VERSION 5.7 ;
  NOWIREEXTENSIONATPIN ON ;
  DIVIDERCHAR "/" ;
  BUSBITCHARS "[]" ;
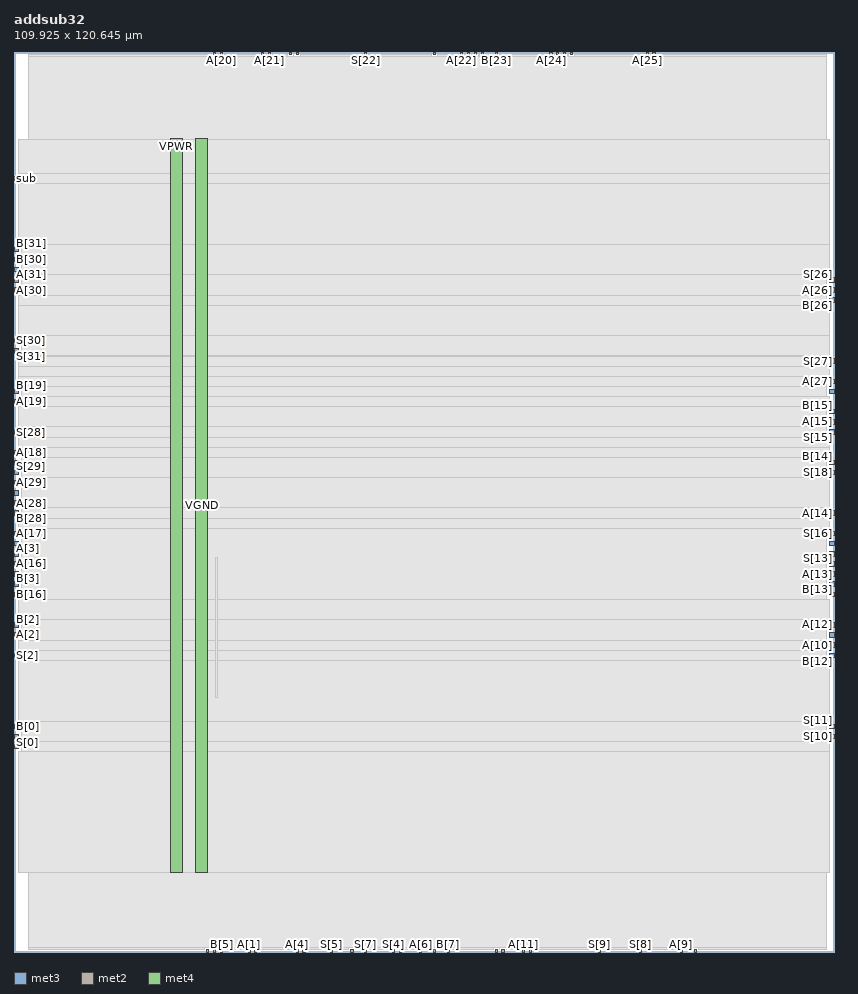
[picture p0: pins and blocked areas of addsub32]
MACRO addsub32
  CLASS BLOCK ;
  FOREIGN addsub32 ;
  ORIGIN 0.000 0.000 ;
  SIZE 109.925 BY 120.645 ;
  PIN A[0]
    DIRECTION INPUT ;
    USE SIGNAL ;
    ANTENNAGATEAREA 0.213000 ;
    PORT
      LAYER met3 ;
        RECT 0.000 27.240 0.600 27.840 ;
    END
  END A[0]
  PIN A[10]
    DIRECTION INPUT ;
    USE SIGNAL ;
    ANTENNAGATEAREA 0.213000 ;
    PORT
      LAYER met3 ;
        RECT 109.325 40.840 109.925 41.440 ;
    END
  END A[10]
  PIN A[11]
    DIRECTION INPUT ;
    USE SIGNAL ;
    ANTENNAGATEAREA 0.213000 ;
    PORT
      LAYER met2 ;
        RECT 68.170 0.000 68.450 0.280 ;
    END
  END A[11]
  PIN A[12]
    DIRECTION INPUT ;
    USE SIGNAL ;
    ANTENNAGATEAREA 0.213000 ;
    PORT
      LAYER met3 ;
        RECT 109.325 43.560 109.925 44.160 ;
    END
  END A[12]
  PIN A[13]
    DIRECTION INPUT ;
    USE SIGNAL ;
    ANTENNAGATEAREA 0.213000 ;
    PORT
      LAYER met3 ;
        RECT 109.325 50.360 109.925 50.960 ;
    END
  END A[13]
  PIN A[14]
    DIRECTION INPUT ;
    USE SIGNAL ;
    ANTENNAGATEAREA 0.213000 ;
    PORT
      LAYER met3 ;
        RECT 109.325 58.520 109.925 59.120 ;
    END
  END A[14]
  PIN A[15]
    DIRECTION INPUT ;
    USE SIGNAL ;
    ANTENNAGATEAREA 0.213000 ;
    PORT
      LAYER met3 ;
        RECT 109.325 70.760 109.925 71.360 ;
    END
  END A[15]
  PIN A[16]
    DIRECTION INPUT ;
    USE SIGNAL ;
    ANTENNAGATEAREA 0.213000 ;
    PORT
      LAYER met3 ;
        RECT 0.000 51.720 0.600 52.320 ;
    END
  END A[16]
  PIN A[17]
    DIRECTION INPUT ;
    USE SIGNAL ;
    ANTENNAGATEAREA 0.213000 ;
    PORT
      LAYER met3 ;
        RECT 0.000 55.800 0.600 56.400 ;
    END
  END A[17]
  PIN A[18]
    DIRECTION INPUT ;
    USE SIGNAL ;
    ANTENNAGATEAREA 0.213000 ;
    PORT
      LAYER met3 ;
        RECT 0.000 66.680 0.600 67.280 ;
    END
  END A[18]
  PIN A[19]
    DIRECTION INPUT ;
    USE SIGNAL ;
    ANTENNAGATEAREA 0.213000 ;
    PORT
      LAYER met3 ;
        RECT 0.000 73.480 0.600 74.080 ;
    END
  END A[19]
  PIN A[1]
    DIRECTION INPUT ;
    USE SIGNAL ;
    ANTENNAGATEAREA 0.213000 ;
    PORT
      LAYER met2 ;
        RECT 31.370 0.000 31.650 0.280 ;
    END
  END A[1]
  PIN A[20]
    DIRECTION INPUT ;
    USE SIGNAL ;
    ANTENNAGATEAREA 0.213000 ;
    PORT
      LAYER met2 ;
        RECT 27.690 120.365 27.970 120.645 ;
    END
  END A[20]
  PIN A[21]
    DIRECTION INPUT ;
    USE SIGNAL ;
    ANTENNAGATEAREA 0.213000 ;
    PORT
      LAYER met2 ;
        RECT 34.130 120.365 34.410 120.645 ;
    END
  END A[21]
  PIN A[22]
    DIRECTION INPUT ;
    USE SIGNAL ;
    ANTENNAGATEAREA 0.213000 ;
    PORT
      LAYER met2 ;
        RECT 59.890 120.365 60.170 120.645 ;
    END
  END A[22]
  PIN A[23]
    DIRECTION INPUT ;
    USE SIGNAL ;
    ANTENNAGATEAREA 0.213000 ;
    PORT
      LAYER met2 ;
        RECT 60.810 120.365 61.090 120.645 ;
    END
  END A[23]
  PIN A[24]
    DIRECTION INPUT ;
    USE SIGNAL ;
    ANTENNAGATEAREA 0.213000 ;
    PORT
      LAYER met2 ;
        RECT 71.850 120.365 72.130 120.645 ;
    END
  END A[24]
  PIN A[25]
    DIRECTION INPUT ;
    USE SIGNAL ;
    ANTENNAGATEAREA 0.213000 ;
    PORT
      LAYER met2 ;
        RECT 84.730 120.365 85.010 120.645 ;
    END
  END A[25]
  PIN A[26]
    DIRECTION INPUT ;
    USE SIGNAL ;
    ANTENNAGATEAREA 0.213000 ;
    PORT
      LAYER met3 ;
        RECT 109.325 88.440 109.925 89.040 ;
    END
  END A[26]
  PIN A[27]
    DIRECTION INPUT ;
    USE SIGNAL ;
    ANTENNAGATEAREA 0.213000 ;
    PORT
      LAYER met3 ;
        RECT 109.325 76.200 109.925 76.800 ;
    END
  END A[27]
  PIN A[28]
    DIRECTION INPUT ;
    USE SIGNAL ;
    ANTENNAGATEAREA 0.213000 ;
    PORT
      LAYER met3 ;
        RECT 0.000 59.880 0.600 60.480 ;
    END
  END A[28]
  PIN A[29]
    DIRECTION INPUT ;
    USE SIGNAL ;
    ANTENNAGATEAREA 0.213000 ;
    PORT
      LAYER met3 ;
        RECT 0.000 62.600 0.600 63.200 ;
    END
  END A[29]
  PIN A[2]
    DIRECTION INPUT ;
    USE SIGNAL ;
    ANTENNAGATEAREA 0.213000 ;
    PORT
      LAYER met3 ;
        RECT 0.000 42.200 0.600 42.800 ;
    END
  END A[2]
  PIN A[30]
    DIRECTION INPUT ;
    USE SIGNAL ;
    ANTENNAGATEAREA 0.213000 ;
    PORT
      LAYER met3 ;
        RECT 0.000 88.440 0.600 89.040 ;
    END
  END A[30]
  PIN A[31]
    DIRECTION INPUT ;
    USE SIGNAL ;
    ANTENNAGATEAREA 0.213000 ;
    PORT
      LAYER met3 ;
        RECT 0.000 89.800 0.600 90.400 ;
    END
  END A[31]
  PIN A[3]
    DIRECTION INPUT ;
    USE SIGNAL ;
    ANTENNAGATEAREA 0.213000 ;
    PORT
      LAYER met3 ;
        RECT 0.000 53.080 0.600 53.680 ;
    END
  END A[3]
  PIN A[4]
    DIRECTION INPUT ;
    USE SIGNAL ;
    ANTENNAGATEAREA 0.213000 ;
    PORT
      LAYER met2 ;
        RECT 37.810 0.000 38.090 0.280 ;
    END
  END A[4]
  PIN A[5]
    DIRECTION INPUT ;
    USE SIGNAL ;
    ANTENNAGATEAREA 0.213000 ;
    PORT
      LAYER met2 ;
        RECT 26.770 0.000 27.050 0.280 ;
    END
  END A[5]
  PIN A[6]
    DIRECTION INPUT ;
    USE SIGNAL ;
    ANTENNAGATEAREA 0.213000 ;
    PORT
      LAYER met2 ;
        RECT 54.370 0.000 54.650 0.280 ;
    END
  END A[6]
  PIN A[7]
    DIRECTION INPUT ;
    USE SIGNAL ;
    ANTENNAGATEAREA 0.213000 ;
    PORT
      LAYER met2 ;
        RECT 56.210 0.000 56.490 0.280 ;
    END
  END A[7]
  PIN A[8]
    DIRECTION INPUT ;
    USE SIGNAL ;
    ANTENNAGATEAREA 0.213000 ;
    PORT
      LAYER met2 ;
        RECT 65.410 0.000 65.690 0.280 ;
    END
  END A[8]
  PIN A[9]
    DIRECTION INPUT ;
    USE SIGNAL ;
    ANTENNAGATEAREA 0.213000 ;
    PORT
      LAYER met2 ;
        RECT 89.330 0.000 89.610 0.280 ;
    END
  END A[9]
  PIN B[0]
    DIRECTION INPUT ;
    USE SIGNAL ;
    ANTENNAGATEAREA 0.126000 ;
    PORT
      LAYER met3 ;
        RECT 0.000 29.960 0.600 30.560 ;
    END
  END B[0]
  PIN B[10]
    DIRECTION INPUT ;
    USE SIGNAL ;
    ANTENNAGATEAREA 0.213000 ;
    PORT
      LAYER met3 ;
        RECT 109.325 42.200 109.925 42.800 ;
    END
  END B[10]
  PIN B[11]
    DIRECTION INPUT ;
    USE SIGNAL ;
    ANTENNAGATEAREA 0.213000 ;
    PORT
      LAYER met2 ;
        RECT 69.090 0.000 69.370 0.280 ;
    END
  END B[11]
  PIN B[12]
    DIRECTION INPUT ;
    USE SIGNAL ;
    ANTENNAGATEAREA 0.213000 ;
    PORT
      LAYER met3 ;
        RECT 109.325 39.480 109.925 40.080 ;
    END
  END B[12]
  PIN B[13]
    DIRECTION INPUT ;
    USE SIGNAL ;
    ANTENNAGATEAREA 0.213000 ;
    PORT
      LAYER met3 ;
        RECT 109.325 49.000 109.925 49.600 ;
    END
  END B[13]
  PIN B[14]
    DIRECTION INPUT ;
    USE SIGNAL ;
    ANTENNAGATEAREA 0.213000 ;
    PORT
      LAYER met3 ;
        RECT 109.325 65.320 109.925 65.920 ;
    END
  END B[14]
  PIN B[15]
    DIRECTION INPUT ;
    USE SIGNAL ;
    ANTENNAGATEAREA 0.213000 ;
    PORT
      LAYER met3 ;
        RECT 109.325 72.120 109.925 72.720 ;
    END
  END B[15]
  PIN B[16]
    DIRECTION INPUT ;
    USE SIGNAL ;
    ANTENNAGATEAREA 0.213000 ;
    PORT
      LAYER met3 ;
        RECT 0.000 47.640 0.600 48.240 ;
    END
  END B[16]
  PIN B[17]
    DIRECTION INPUT ;
    USE SIGNAL ;
    ANTENNAGATEAREA 0.213000 ;
    PORT
      LAYER met3 ;
        RECT 0.000 54.440 0.600 55.040 ;
    END
  END B[17]
  PIN B[18]
    DIRECTION INPUT ;
    USE SIGNAL ;
    ANTENNAGATEAREA 0.213000 ;
    PORT
      LAYER met3 ;
        RECT 0.000 65.320 0.600 65.920 ;
    END
  END B[18]
  PIN B[19]
    DIRECTION INPUT ;
    USE SIGNAL ;
    ANTENNAGATEAREA 0.213000 ;
    PORT
      LAYER met3 ;
        RECT 0.000 74.840 0.600 75.440 ;
    END
  END B[19]
  PIN B[1]
    DIRECTION INPUT ;
    USE SIGNAL ;
    ANTENNAGATEAREA 0.213000 ;
    PORT
      LAYER met2 ;
        RECT 32.290 0.000 32.570 0.280 ;
    END
  END B[1]
  PIN B[20]
    DIRECTION INPUT ;
    USE SIGNAL ;
    ANTENNAGATEAREA 0.213000 ;
    PORT
      LAYER met2 ;
        RECT 26.770 120.365 27.050 120.645 ;
    END
  END B[20]
  PIN B[21]
    DIRECTION INPUT ;
    USE SIGNAL ;
    ANTENNAGATEAREA 0.213000 ;
    PORT
      LAYER met2 ;
        RECT 33.210 120.365 33.490 120.645 ;
    END
  END B[21]
  PIN B[22]
    DIRECTION INPUT ;
    USE SIGNAL ;
    ANTENNAGATEAREA 0.213000 ;
    PORT
      LAYER met2 ;
        RECT 62.650 120.365 62.930 120.645 ;
    END
  END B[22]
  PIN B[23]
    DIRECTION INPUT ;
    USE SIGNAL ;
    ANTENNAGATEAREA 0.213000 ;
    PORT
      LAYER met2 ;
        RECT 64.490 120.365 64.770 120.645 ;
    END
  END B[23]
  PIN B[24]
    DIRECTION INPUT ;
    USE SIGNAL ;
    ANTENNAGATEAREA 0.213000 ;
    PORT
      LAYER met2 ;
        RECT 73.690 120.365 73.970 120.645 ;
    END
  END B[24]
  PIN B[25]
    DIRECTION INPUT ;
    USE SIGNAL ;
    ANTENNAGATEAREA 0.213000 ;
    PORT
      LAYER met2 ;
        RECT 85.650 120.365 85.930 120.645 ;
    END
  END B[25]
  PIN B[26]
    DIRECTION INPUT ;
    USE SIGNAL ;
    ANTENNAGATEAREA 0.213000 ;
    PORT
      LAYER met3 ;
        RECT 109.325 87.080 109.925 87.680 ;
    END
  END B[26]
  PIN B[27]
    DIRECTION INPUT ;
    USE SIGNAL ;
    ANTENNAGATEAREA 0.213000 ;
    PORT
      LAYER met3 ;
        RECT 109.325 74.840 109.925 75.440 ;
    END
  END B[27]
  PIN B[28]
    DIRECTION INPUT ;
    USE SIGNAL ;
    ANTENNAGATEAREA 0.213000 ;
    PORT
      LAYER met3 ;
        RECT 0.000 58.520 0.600 59.120 ;
    END
  END B[28]
  PIN B[29]
    DIRECTION INPUT ;
    USE SIGNAL ;
    ANTENNAGATEAREA 0.213000 ;
    PORT
      LAYER met3 ;
        RECT 0.000 61.240 0.600 61.840 ;
    END
  END B[29]
  PIN B[2]
    DIRECTION INPUT ;
    USE SIGNAL ;
    ANTENNAGATEAREA 0.213000 ;
    PORT
      LAYER met3 ;
        RECT 0.000 43.560 0.600 44.160 ;
    END
  END B[2]
  PIN B[30]
    DIRECTION INPUT ;
    USE SIGNAL ;
    ANTENNAGATEAREA 0.213000 ;
    PORT
      LAYER met3 ;
        RECT 0.000 92.520 0.600 93.120 ;
    END
  END B[30]
  PIN B[31]
    DIRECTION INPUT ;
    USE SIGNAL ;
    ANTENNAGATEAREA 0.213000 ;
    PORT
      LAYER met3 ;
        RECT 0.000 93.880 0.600 94.480 ;
    END
  END B[31]
  PIN B[3]
    DIRECTION INPUT ;
    USE SIGNAL ;
    ANTENNAGATEAREA 0.213000 ;
    PORT
      LAYER met3 ;
        RECT 0.000 49.000 0.600 49.600 ;
    END
  END B[3]
  PIN B[4]
    DIRECTION INPUT ;
    USE SIGNAL ;
    ANTENNAGATEAREA 0.213000 ;
    PORT
      LAYER met2 ;
        RECT 38.730 0.000 39.010 0.280 ;
    END
  END B[4]
  PIN B[5]
    DIRECTION INPUT ;
    USE SIGNAL ;
    ANTENNAGATEAREA 0.213000 ;
    PORT
      LAYER met2 ;
        RECT 27.690 0.000 27.970 0.280 ;
    END
  END B[5]
  PIN B[6]
    DIRECTION INPUT ;
    USE SIGNAL ;
    ANTENNAGATEAREA 0.213000 ;
    PORT
      LAYER met2 ;
        RECT 51.610 0.000 51.890 0.280 ;
    END
  END B[6]
  PIN B[7]
    DIRECTION INPUT ;
    USE SIGNAL ;
    ANTENNAGATEAREA 0.213000 ;
    PORT
      LAYER met2 ;
        RECT 58.050 0.000 58.330 0.280 ;
    END
  END B[7]
  PIN B[8]
    DIRECTION INPUT ;
    USE SIGNAL ;
    ANTENNAGATEAREA 0.213000 ;
    PORT
      LAYER met2 ;
        RECT 64.490 0.000 64.770 0.280 ;
    END
  END B[8]
  PIN B[9]
    DIRECTION INPUT ;
    USE SIGNAL ;
    ANTENNAGATEAREA 0.213000 ;
    PORT
      LAYER met2 ;
        RECT 91.170 0.000 91.450 0.280 ;
    END
  END B[9]
  PIN S[0]
    DIRECTION OUTPUT ;
    USE SIGNAL ;
    ANTENNADIFFAREA 0.702900 ;
    PORT
      LAYER met3 ;
        RECT 0.000 28.600 0.600 29.200 ;
    END
  END S[0]
  PIN S[10]
    DIRECTION OUTPUT ;
    USE SIGNAL ;
    ANTENNAGATEAREA 0.126000 ;
    ANTENNADIFFAREA 0.429000 ;
    PORT
      LAYER met3 ;
        RECT 109.325 28.600 109.925 29.200 ;
    END
  END S[10]
  PIN S[11]
    DIRECTION OUTPUT ;
    USE SIGNAL ;
    ANTENNADIFFAREA 0.383400 ;
    PORT
      LAYER met3 ;
        RECT 109.325 29.960 109.925 30.560 ;
    END
  END S[11]
  PIN S[12]
    DIRECTION OUTPUT ;
    USE SIGNAL ;
    ANTENNAGATEAREA 0.126000 ;
    ANTENNADIFFAREA 0.429000 ;
    PORT
      LAYER met3 ;
        RECT 109.325 47.640 109.925 48.240 ;
    END
  END S[12]
  PIN S[13]
    DIRECTION OUTPUT ;
    USE SIGNAL ;
    ANTENNAGATEAREA 0.126000 ;
    ANTENNADIFFAREA 0.429000 ;
    PORT
      LAYER met3 ;
        RECT 109.325 51.720 109.925 52.320 ;
    END
  END S[13]
  PIN S[14]
    DIRECTION OUTPUT ;
    USE SIGNAL ;
    ANTENNADIFFAREA 0.795200 ;
    PORT
      LAYER met3 ;
        RECT 109.325 53.080 109.925 53.680 ;
    END
  END S[14]
  PIN S[15]
    DIRECTION OUTPUT ;
    USE SIGNAL ;
    ANTENNADIFFAREA 0.383400 ;
    PORT
      LAYER met3 ;
        RECT 109.325 69.400 109.925 70.000 ;
    END
  END S[15]
  PIN S[16]
    DIRECTION OUTPUT ;
    USE SIGNAL ;
    ANTENNADIFFAREA 1.336500 ;
    PORT
      LAYER met3 ;
        RECT 109.325 55.800 109.925 56.400 ;
    END
  END S[16]
  PIN S[17]
    DIRECTION OUTPUT ;
    USE SIGNAL ;
    ANTENNADIFFAREA 1.336500 ;
    PORT
      LAYER met3 ;
        RECT 109.325 54.440 109.925 55.040 ;
    END
  END S[17]
  PIN S[18]
    DIRECTION OUTPUT ;
    USE SIGNAL ;
    ANTENNADIFFAREA 0.795200 ;
    PORT
      LAYER met3 ;
        RECT 109.325 63.960 109.925 64.560 ;
    END
  END S[18]
  PIN S[19]
    DIRECTION OUTPUT ;
    USE SIGNAL ;
    ANTENNADIFFAREA 0.795200 ;
    PORT
      LAYER met2 ;
        RECT 56.210 120.365 56.490 120.645 ;
    END
  END S[19]
  PIN S[1]
    DIRECTION OUTPUT ;
    USE SIGNAL ;
    ANTENNAGATEAREA 0.126000 ;
    ANTENNADIFFAREA 0.429000 ;
    PORT
      LAYER met2 ;
        RECT 25.850 0.000 26.130 0.280 ;
    END
  END S[1]
  PIN S[20]
    DIRECTION OUTPUT ;
    USE SIGNAL ;
    ANTENNADIFFAREA 1.336500 ;
    PORT
      LAYER met2 ;
        RECT 37.810 120.365 38.090 120.645 ;
    END
  END S[20]
  PIN S[21]
    DIRECTION OUTPUT ;
    USE SIGNAL ;
    ANTENNADIFFAREA 1.782000 ;
    PORT
      LAYER met2 ;
        RECT 36.890 120.365 37.170 120.645 ;
    END
  END S[21]
  PIN S[22]
    DIRECTION OUTPUT ;
    USE SIGNAL ;
    ANTENNADIFFAREA 1.336500 ;
    PORT
      LAYER met2 ;
        RECT 47.010 120.365 47.290 120.645 ;
    END
  END S[22]
  PIN S[23]
    DIRECTION OUTPUT ;
    USE SIGNAL ;
    ANTENNADIFFAREA 0.891000 ;
    PORT
      LAYER met2 ;
        RECT 61.730 120.365 62.010 120.645 ;
    END
  END S[23]
  PIN S[24]
    DIRECTION OUTPUT ;
    USE SIGNAL ;
    ANTENNADIFFAREA 1.336500 ;
    PORT
      LAYER met2 ;
        RECT 72.770 120.365 73.050 120.645 ;
    END
  END S[24]
  PIN S[25]
    DIRECTION OUTPUT ;
    USE SIGNAL ;
    ANTENNADIFFAREA 1.336500 ;
    PORT
      LAYER met2 ;
        RECT 74.610 120.365 74.890 120.645 ;
    END
  END S[25]
  PIN S[26]
    DIRECTION OUTPUT ;
    USE SIGNAL ;
    ANTENNADIFFAREA 1.336500 ;
    PORT
      LAYER met3 ;
        RECT 109.325 89.800 109.925 90.400 ;
    END
  END S[26]
  PIN S[27]
    DIRECTION OUTPUT ;
    USE SIGNAL ;
    ANTENNADIFFAREA 1.336500 ;
    PORT
      LAYER met3 ;
        RECT 109.325 78.920 109.925 79.520 ;
    END
  END S[27]
  PIN S[28]
    DIRECTION OUTPUT ;
    USE SIGNAL ;
    ANTENNADIFFAREA 1.336500 ;
    PORT
      LAYER met3 ;
        RECT 0.000 69.400 0.600 70.000 ;
    END
  END S[28]
  PIN S[29]
    DIRECTION OUTPUT ;
    USE SIGNAL ;
    ANTENNADIFFAREA 1.336500 ;
    PORT
      LAYER met3 ;
        RECT 0.000 63.960 0.600 64.560 ;
    END
  END S[29]
  PIN S[2]
    DIRECTION OUTPUT ;
    USE SIGNAL ;
    ANTENNADIFFAREA 0.891000 ;
    PORT
      LAYER met3 ;
        RECT 0.000 39.480 0.600 40.080 ;
    END
  END S[2]
  PIN S[30]
    DIRECTION OUTPUT ;
    USE SIGNAL ;
    ANTENNADIFFAREA 1.336500 ;
    PORT
      LAYER met3 ;
        RECT 0.000 81.640 0.600 82.240 ;
    END
  END S[30]
  PIN S[31]
    DIRECTION OUTPUT ;
    USE SIGNAL ;
    ANTENNADIFFAREA 1.336500 ;
    PORT
      LAYER met3 ;
        RECT 0.000 80.280 0.600 80.880 ;
    END
  END S[31]
  PIN S[3]
    DIRECTION OUTPUT ;
    USE SIGNAL ;
    ANTENNADIFFAREA 1.336500 ;
    PORT
      LAYER met3 ;
        RECT 0.000 50.360 0.600 50.960 ;
    END
  END S[3]
  PIN S[4]
    DIRECTION OUTPUT ;
    USE SIGNAL ;
    ANTENNADIFFAREA 0.383400 ;
    PORT
      LAYER met2 ;
        RECT 50.690 0.000 50.970 0.280 ;
    END
  END S[4]
  PIN S[5]
    DIRECTION OUTPUT ;
    USE SIGNAL ;
    ANTENNADIFFAREA 0.445500 ;
    PORT
      LAYER met2 ;
        RECT 42.410 0.000 42.690 0.280 ;
    END
  END S[5]
  PIN S[6]
    DIRECTION OUTPUT ;
    USE SIGNAL ;
    ANTENNADIFFAREA 1.336500 ;
    PORT
      LAYER met2 ;
        RECT 45.170 0.000 45.450 0.280 ;
    END
  END S[6]
  PIN S[7]
    DIRECTION OUTPUT ;
    USE SIGNAL ;
    ANTENNADIFFAREA 0.445500 ;
    PORT
      LAYER met2 ;
        RECT 47.010 0.000 47.290 0.280 ;
    END
  END S[7]
  PIN S[8]
    DIRECTION OUTPUT ;
    USE SIGNAL ;
    ANTENNADIFFAREA 0.383400 ;
    PORT
      LAYER met2 ;
        RECT 83.810 0.000 84.090 0.280 ;
    END
  END S[8]
  PIN S[9]
    DIRECTION OUTPUT ;
    USE SIGNAL ;
    ANTENNADIFFAREA 0.383400 ;
    PORT
      LAYER met2 ;
        RECT 78.290 0.000 78.570 0.280 ;
    END
  END S[9]
  PIN VGND
    DIRECTION INOUT ;
    USE GROUND ;
    PORT
      LAYER met4 ;
        RECT 24.340 10.640 25.940 109.040 ;
    END
  END VGND
  PIN VPWR
    DIRECTION INOUT ;
    USE POWER ;
    PORT
      LAYER met4 ;
        RECT 21.040 10.640 22.640 109.040 ;
    END
  END VPWR
  PIN carryOut
    DIRECTION OUTPUT ;
    USE SIGNAL ;
    ANTENNADIFFAREA 1.336500 ;
    PORT
      LAYER met3 ;
        RECT 0.000 91.160 0.600 91.760 ;
    END
  END carryOut
  PIN sub
    DIRECTION INPUT ;
    USE SIGNAL ;
    ANTENNAGATEAREA 0.742500 ;
    PORT
      LAYER met3 ;
        RECT 0.000 103.400 0.600 104.000 ;
    END
  END sub
  OBS
      LAYER nwell ;
        RECT 5.330 10.795 104.150 108.885 ;
      LAYER li1 ;
        RECT 5.520 10.795 103.960 108.885 ;
      LAYER met1 ;
        RECT 1.910 5.480 108.950 117.940 ;
      LAYER met2 ;
        RECT 1.930 120.085 26.490 120.365 ;
        RECT 27.330 120.085 27.410 120.365 ;
        RECT 28.250 120.085 32.930 120.365 ;
        RECT 33.770 120.085 33.850 120.365 ;
        RECT 34.690 120.085 36.610 120.365 ;
        RECT 37.450 120.085 37.530 120.365 ;
        RECT 38.370 120.085 46.730 120.365 ;
        RECT 47.570 120.085 55.930 120.365 ;
        RECT 56.770 120.085 59.610 120.365 ;
        RECT 60.450 120.085 60.530 120.365 ;
        RECT 61.370 120.085 61.450 120.365 ;
        RECT 62.290 120.085 62.370 120.365 ;
        RECT 63.210 120.085 64.210 120.365 ;
        RECT 65.050 120.085 71.570 120.365 ;
        RECT 72.410 120.085 72.490 120.365 ;
        RECT 73.330 120.085 73.410 120.365 ;
        RECT 74.250 120.085 74.330 120.365 ;
        RECT 75.170 120.085 84.450 120.365 ;
        RECT 85.290 120.085 85.370 120.365 ;
        RECT 86.210 120.085 108.930 120.365 ;
        RECT 1.930 0.560 108.930 120.085 ;
        RECT 1.930 0.280 25.570 0.560 ;
        RECT 26.410 0.280 26.490 0.560 ;
        RECT 27.330 0.280 27.410 0.560 ;
        RECT 28.250 0.280 31.090 0.560 ;
        RECT 31.930 0.280 32.010 0.560 ;
        RECT 32.850 0.280 37.530 0.560 ;
        RECT 38.370 0.280 38.450 0.560 ;
        RECT 39.290 0.280 42.130 0.560 ;
        RECT 42.970 0.280 44.890 0.560 ;
        RECT 45.730 0.280 46.730 0.560 ;
        RECT 47.570 0.280 50.410 0.560 ;
        RECT 51.250 0.280 51.330 0.560 ;
        RECT 52.170 0.280 54.090 0.560 ;
        RECT 54.930 0.280 55.930 0.560 ;
        RECT 56.770 0.280 57.770 0.560 ;
        RECT 58.610 0.280 64.210 0.560 ;
        RECT 65.050 0.280 65.130 0.560 ;
        RECT 65.970 0.280 67.890 0.560 ;
        RECT 68.730 0.280 68.810 0.560 ;
        RECT 69.650 0.280 78.010 0.560 ;
        RECT 78.850 0.280 83.530 0.560 ;
        RECT 84.370 0.280 89.050 0.560 ;
        RECT 89.890 0.280 90.890 0.560 ;
        RECT 91.730 0.280 108.930 0.560 ;
      LAYER met3 ;
        RECT 0.600 104.400 109.325 108.965 ;
        RECT 1.000 103.000 109.325 104.400 ;
        RECT 0.600 94.880 109.325 103.000 ;
        RECT 1.000 90.800 109.325 94.880 ;
        RECT 1.000 88.040 108.925 90.800 ;
        RECT 0.600 86.680 108.925 88.040 ;
        RECT 0.600 82.640 109.325 86.680 ;
        RECT 1.000 79.920 109.325 82.640 ;
        RECT 1.000 79.880 108.925 79.920 ;
        RECT 0.600 78.520 108.925 79.880 ;
        RECT 0.600 77.200 109.325 78.520 ;
        RECT 0.600 75.840 108.925 77.200 ;
        RECT 1.000 74.440 108.925 75.840 ;
        RECT 1.000 73.120 109.325 74.440 ;
        RECT 1.000 73.080 108.925 73.120 ;
        RECT 0.600 70.400 108.925 73.080 ;
        RECT 1.000 69.000 108.925 70.400 ;
        RECT 0.600 67.680 109.325 69.000 ;
        RECT 1.000 66.320 109.325 67.680 ;
        RECT 1.000 63.560 108.925 66.320 ;
        RECT 1.000 59.520 109.325 63.560 ;
        RECT 1.000 58.120 108.925 59.520 ;
        RECT 0.600 56.800 109.325 58.120 ;
        RECT 1.000 47.240 108.925 56.800 ;
        RECT 0.600 44.560 109.325 47.240 ;
        RECT 1.000 41.800 108.925 44.560 ;
        RECT 0.600 40.480 108.925 41.800 ;
        RECT 1.000 39.080 108.925 40.480 ;
        RECT 0.600 30.960 109.325 39.080 ;
        RECT 1.000 28.200 108.925 30.960 ;
        RECT 1.000 26.840 109.325 28.200 ;
        RECT 0.600 10.715 109.325 26.840 ;
      LAYER met4 ;
        RECT 26.975 34.175 27.305 52.865 ;
  END
END addsub32
END LIBRARY

